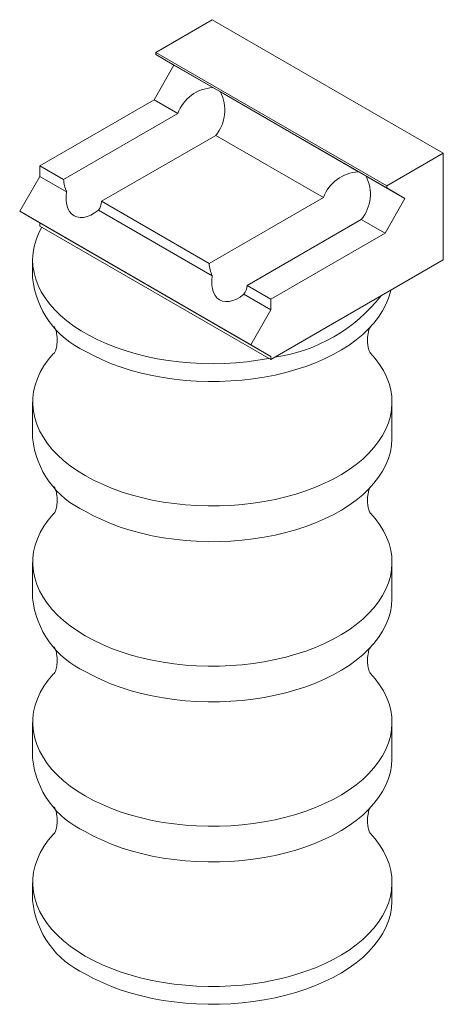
# Model space of a CAD drawing. Units: inches. Extents: x -0.3 to 1.33, y -3.33 to 0.43.
import ezdxf

# ---------------------------------------------------------------- set-up
doc = ezdxf.new("R2010")
doc.units = ezdxf.units.IN
doc.header["$MEASUREMENT"] = 0

msp = doc.modelspace()

# ---------------------------------------------------------------- linework, layer by layer
at = {"color": 7, "linetype": 'Continuous', "lineweight": 15}
for p, q in [((0.4419, 0.4323), (0.2252, 0.3072)), ((1.3258, -0.0779), (0.4419, 0.4323)), ((0.2252, 0.299), (0.2252, 0.3072)), ((1.1091, -0.2031), (0.2252, 0.3072)), ((1.1091, -0.2112), (0.2252, 0.299)), ((0.2252, 0.299), (0.2952, 0.2586)), ((0.2952, 0.2586), (0.2188, 0.1263)), ((0.4443, 0.1726), (0.2952, 0.2586)), ((1.0015, -0.1491), (0.4728, 0.1561)), ((0.2188, 0.1263), (-0.2181, -0.1259)), ((0.3095, 0.074), (0.2188, 0.1263)), ((-0.1275, -0.1783), (0.3095, 0.074)), ((0.4549, -0.0099), (0.0179, -0.2622)), ((0.8667, -0.2477), (0.4549, -0.0099)), ((1.3258, -0.0779), (1.1091, -0.2031)), ((1.3258, -0.4862), (1.3258, -0.0779)), ((-0.2181, -0.1259), (-0.1275, -0.1783)), ((-0.2181, -0.1668), (-0.2181, -0.1259)), ((-0.2952, -0.3003), (-0.2181, -0.1668)), ((-0.1155, -0.226), (-0.2181, -0.1668)), ((1.1791, -0.2516), (1.03, -0.1656)), ((1.1091, -0.2031), (1.1091, -0.2112)), ((1.1091, -0.2112), (1.1791, -0.2516)), ((0.0179, -0.2622), (0.4297, -0.4999)), ((0.4297, -0.4999), (0.8667, -0.2477)), ((1.1791, -0.2516), (1.1027, -0.3839)), ((0.5887, -0.8105), (-0.2952, -0.3003)), ((-0.2181, -0.3448), (-0.2952, -0.3003)), ((0.4417, -0.5477), (0.0059, -0.2961)), ((1.0121, -0.3316), (0.5751, -0.5838)), ((1.1027, -0.3839), (1.0121, -0.3316)), ((0.6657, -0.855), (-0.2181, -0.3448)), ((-0.2181, -0.357), (-0.2181, -0.3448)), ((0.6657, -0.8673), (-0.2181, -0.357)), ((1.1027, -0.3839), (0.6657, -0.6362)), ((-0.2456, -0.4862), (-0.2456, -0.5544)), ((0.6657, -0.8673), (1.3258, -0.4862)), ((0.5751, -0.5838), (0.6657, -0.6362)), ((0.6657, -0.677), (0.5631, -0.6177)), ((0.6657, -0.6362), (0.6657, -0.677)), ((0.6657, -0.677), (0.5887, -0.8105)), ((0.5887, -0.8105), (0.6657, -0.855)), ((0.6657, -0.855), (0.6657, -0.8673)), ((-0.2456, -1.0304), (-0.2456, -1.1668)), ((1.1294, -1.1668), (1.1294, -1.0304)), ((-0.2456, -1.6428), (-0.2456, -1.7792)), ((1.1294, -1.7792), (1.1294, -1.6428)), ((-0.2456, -2.2552), (-0.2456, -2.3916)), ((1.1294, -2.3916), (1.1294, -2.2552)), ((-0.2456, -2.8676), (-0.2456, -2.9358)), ((1.1294, -2.9358), (1.1294, -2.8676))]:
    msp.add_line(p, q, dxfattribs=at)
at = {"color": 7, "linetype": 'Continuous', "lineweight": 15, "flags": 128}
for points in [[(0.4728, 0.1561), (0.4621, 0.1623), (0.4525, 0.1678), (0.4443, 0.1726)], [(1.03, -0.1656), (1.0193, -0.1594), (1.0097, -0.1539), (1.0015, -0.1491)], [(0.0059, -0.2961), (-0.0085, -0.3065), (-0.023, -0.3147), (-0.0373, -0.3204), (-0.0511, -0.3235), (-0.0643, -0.3241), (-0.0764, -0.322), (-0.0873, -0.3174), (-0.0968, -0.3103), (-0.1047, -0.3008), (-0.1108, -0.2891), (-0.1149, -0.2755), (-0.1171, -0.2603), (-0.1173, -0.2437), (-0.1155, -0.226)], [(-0.2106, -0.3613), (-0.223, -0.3854), (-0.2327, -0.4098), (-0.2397, -0.4345), (-0.244, -0.4595), (-0.2456, -0.4845), (-0.2444, -0.5096), (-0.2404, -0.5346), (-0.2338, -0.5593), (-0.2244, -0.5838), (-0.2124, -0.6079), (-0.1978, -0.6315), (-0.1807, -0.6545), (-0.161, -0.6769), (-0.139, -0.6985), (-0.1146, -0.7192), (-0.088, -0.739), (-0.0593, -0.7578), (-0.0286, -0.7756), (0.004, -0.7921), (0.0383, -0.8075), (0.0742, -0.8216), (0.1117, -0.8343), (0.1504, -0.8456), (0.1903, -0.8555), (0.2311, -0.864), (0.2729, -0.8709), (0.3153, -0.8763), (0.3582, -0.8801), (0.4014, -0.8824), (0.4448, -0.8831), (0.4882, -0.8822), (0.5314, -0.8797), (0.5743, -0.8757), (0.6166, -0.8701), (0.6582, -0.8629)], [(0.5631, -0.6177), (0.5487, -0.6282), (0.5342, -0.6363), (0.5199, -0.642), (0.5061, -0.6452), (0.4929, -0.6458), (0.4808, -0.6437), (0.4699, -0.6391), (0.4604, -0.6319), (0.4525, -0.6224), (0.4464, -0.6108), (0.4423, -0.5972), (0.4401, -0.582), (0.4399, -0.5653), (0.4417, -0.5477)], [(-0.0442, -0.835), (-0.0124, -0.8523), (0.0213, -0.8683), (0.0566, -0.8831), (0.0935, -0.8965), (0.1318, -0.9086), (0.1713, -0.9192), (0.2119, -0.9284), (0.2535, -0.9361), (0.2958, -0.9422), (0.3387, -0.9468), (0.382, -0.9498), (0.4256, -0.9512), (0.4692, -0.951), (0.5127, -0.9492), (0.5559, -0.9458), (0.5987, -0.9408), (0.6409, -0.9343), (0.6822, -0.9263), (0.7226, -0.9167), (0.7618, -0.9057), (0.7998, -0.8933), (0.8363, -0.8795), (0.8712, -0.8644), (0.9044, -0.8481), (0.9357, -0.8306), (0.9651, -0.8119), (0.9923, -0.7923), (1.0173, -0.7716), (1.04, -0.7501), (1.0603, -0.7278), (1.0781, -0.7048), (1.0934, -0.6812), (1.106, -0.6571), (1.116, -0.6326), (1.1232, -0.6078), (1.1244, -0.6025)], [(-0.1635, -0.8424), (-0.1666, -0.8458), (-0.1857, -0.8684), (-0.2022, -0.8917), (-0.2162, -0.9156), (-0.2274, -0.9399), (-0.236, -0.9646), (-0.2419, -0.9896), (-0.245, -1.0147), (-0.2454, -1.0399), (-0.2429, -1.065), (-0.2378, -1.09), (-0.2298, -1.1148), (-0.2192, -1.1392), (-0.2059, -1.1632), (-0.19, -1.1867), (-0.1716, -1.2095), (-0.1507, -1.2316), (-0.1274, -1.2529), (-0.1018, -1.2733), (-0.074, -1.2927), (-0.0442, -1.3111)], [(-0.0442, -1.3111), (-0.0124, -1.3283), (0.0213, -1.3443), (0.0566, -1.3591), (0.0935, -1.3725), (0.1318, -1.3846), (0.1713, -1.3953), (0.2119, -1.4044), (0.2535, -1.4121), (0.2958, -1.4182), (0.3387, -1.4228), (0.382, -1.4258), (0.4256, -1.4272), (0.4692, -1.427), (0.5127, -1.4252), (0.5559, -1.4218), (0.5987, -1.4168), (0.6409, -1.4103), (0.6822, -1.4023), (0.7226, -1.3927), (0.7618, -1.3817), (0.7998, -1.3693), (0.8363, -1.3555), (0.8712, -1.3404), (0.9044, -1.3241), (0.9357, -1.3066), (0.9651, -1.2879), (0.9923, -1.2683), (1.0173, -1.2476), (1.04, -1.2261), (1.0603, -1.2038), (1.0781, -1.1808), (1.0934, -1.1572), (1.106, -1.1331), (1.116, -1.1086), (1.1232, -1.0838), (1.1277, -1.0587), (1.1294, -1.0336), (1.1284, -1.0084), (1.1246, -0.9833), (1.118, -0.9584), (1.1088, -0.9338), (1.0968, -0.9096), (1.0822, -0.8858), (1.065, -0.8627), (1.0477, -0.8427)], [(-0.0442, -1.4475), (-0.0124, -1.4647), (0.0213, -1.4807), (0.0566, -1.4955), (0.0935, -1.5089), (0.1318, -1.521), (0.1713, -1.5317), (0.2119, -1.5408), (0.2535, -1.5485), (0.2958, -1.5546), (0.3387, -1.5592), (0.382, -1.5622), (0.4256, -1.5636), (0.4692, -1.5634), (0.5127, -1.5616), (0.5559, -1.5582), (0.5987, -1.5532), (0.6409, -1.5467), (0.6822, -1.5387), (0.7226, -1.5291), (0.7618, -1.5181), (0.7998, -1.5057), (0.8363, -1.4919), (0.8712, -1.4768), (0.9044, -1.4605), (0.9357, -1.443), (0.9651, -1.4243), (0.9923, -1.4047), (1.0173, -1.384), (1.04, -1.3625), (1.0603, -1.3402), (1.0781, -1.3172), (1.0934, -1.2936), (1.106, -1.2695), (1.116, -1.245), (1.1232, -1.2202), (1.1277, -1.1951), (1.1294, -1.17), (1.1294, -1.1668)], [(-0.1635, -1.4548), (-0.1666, -1.4582), (-0.1857, -1.4808), (-0.2022, -1.5041), (-0.2162, -1.528), (-0.2274, -1.5523), (-0.236, -1.577), (-0.2419, -1.602), (-0.245, -1.6271), (-0.2454, -1.6523), (-0.2429, -1.6774), (-0.2378, -1.7024), (-0.2298, -1.7272), (-0.2192, -1.7516), (-0.2059, -1.7756), (-0.19, -1.7991), (-0.1716, -1.8219), (-0.1507, -1.844), (-0.1274, -1.8653), (-0.1018, -1.8857), (-0.074, -1.9051), (-0.0442, -1.9235)], [(-0.0442, -1.9235), (-0.0124, -1.9407), (0.0213, -1.9567), (0.0566, -1.9715), (0.0935, -1.985), (0.1318, -1.997), (0.1713, -2.0077), (0.2119, -2.0168), (0.2535, -2.0245), (0.2958, -2.0306), (0.3387, -2.0352), (0.382, -2.0382), (0.4256, -2.0396), (0.4692, -2.0394), (0.5127, -2.0376), (0.5559, -2.0342), (0.5987, -2.0293), (0.6409, -2.0227), (0.6822, -2.0147), (0.7226, -2.0051), (0.7618, -1.9941), (0.7998, -1.9817), (0.8363, -1.9679), (0.8712, -1.9528), (0.9044, -1.9365), (0.9357, -1.919), (0.9651, -1.9003), (0.9923, -1.8807), (1.0173, -1.86), (1.04, -1.8385), (1.0603, -1.8162), (1.0781, -1.7932), (1.0934, -1.7697), (1.106, -1.7455), (1.116, -1.721), (1.1232, -1.6962), (1.1277, -1.6711), (1.1294, -1.646), (1.1284, -1.6208), (1.1246, -1.5957), (1.118, -1.5708), (1.1088, -1.5462), (1.0968, -1.522), (1.0822, -1.4982), (1.065, -1.4751), (1.0477, -1.4551)], [(-0.0442, -2.0599), (-0.0124, -2.0771), (0.0213, -2.0931), (0.0566, -2.1079), (0.0935, -2.1213), (0.1318, -2.1334), (0.1713, -2.1441), (0.2119, -2.1532), (0.2535, -2.1609), (0.2958, -2.167), (0.3387, -2.1716), (0.382, -2.1746), (0.4256, -2.176), (0.4692, -2.1758), (0.5127, -2.174), (0.5559, -2.1706), (0.5987, -2.1656), (0.6409, -2.1591), (0.6822, -2.1511), (0.7226, -2.1415), (0.7618, -2.1305), (0.7998, -2.1181), (0.8363, -2.1043), (0.8712, -2.0892), (0.9044, -2.0729), (0.9357, -2.0554), (0.9651, -2.0367), (0.9923, -2.0171), (1.0173, -1.9964), (1.04, -1.9749), (1.0603, -1.9526), (1.0781, -1.9296), (1.0934, -1.906), (1.106, -1.8819), (1.116, -1.8574), (1.1232, -1.8326), (1.1277, -1.8075), (1.1294, -1.7824), (1.1294, -1.7792)], [(-0.1635, -2.0672), (-0.1666, -2.0706), (-0.1857, -2.0932), (-0.2022, -2.1165), (-0.2162, -2.1404), (-0.2274, -2.1647), (-0.236, -2.1894), (-0.2419, -2.2144), (-0.245, -2.2395), (-0.2454, -2.2647), (-0.2429, -2.2898), (-0.2378, -2.3148), (-0.2298, -2.3396), (-0.2192, -2.364), (-0.2059, -2.388), (-0.19, -2.4115), (-0.1716, -2.4343), (-0.1507, -2.4564), (-0.1274, -2.4777), (-0.1018, -2.4981), (-0.074, -2.5175), (-0.0442, -2.5359)], [(-0.0442, -2.5359), (-0.0124, -2.5531), (0.0213, -2.5691), (0.0566, -2.5839), (0.0935, -2.5974), (0.1318, -2.6094), (0.1713, -2.6201), (0.2119, -2.6292), (0.2535, -2.6369), (0.2958, -2.643), (0.3387, -2.6476), (0.382, -2.6506), (0.4256, -2.652), (0.4692, -2.6518), (0.5127, -2.65), (0.5559, -2.6466), (0.5987, -2.6417), (0.6409, -2.6351), (0.6822, -2.6271), (0.7226, -2.6175), (0.7618, -2.6065), (0.7998, -2.5941), (0.8363, -2.5803), (0.8712, -2.5652), (0.9044, -2.5489), (0.9357, -2.5314), (0.9651, -2.5127), (0.9923, -2.4931), (1.0173, -2.4724), (1.04, -2.4509), (1.0603, -2.4286), (1.0781, -2.4057), (1.0934, -2.3821), (1.106, -2.3579), (1.116, -2.3334), (1.1232, -2.3086), (1.1277, -2.2835), (1.1294, -2.2584), (1.1284, -2.2332), (1.1246, -2.2081), (1.118, -2.1832), (1.1088, -2.1586), (1.0968, -2.1344), (1.0822, -2.1106), (1.065, -2.0875), (1.0477, -2.0675)], [(-0.0442, -2.6723), (-0.0124, -2.6895), (0.0213, -2.7055), (0.0566, -2.7203), (0.0935, -2.7338), (0.1318, -2.7458), (0.1713, -2.7565), (0.2119, -2.7656), (0.2535, -2.7733), (0.2958, -2.7794), (0.3387, -2.784), (0.382, -2.787), (0.4256, -2.7884), (0.4692, -2.7882), (0.5127, -2.7864), (0.5559, -2.783), (0.5987, -2.7781), (0.6409, -2.7715), (0.6822, -2.7635), (0.7226, -2.7539), (0.7618, -2.7429), (0.7998, -2.7305), (0.8363, -2.7167), (0.8712, -2.7016), (0.9044, -2.6853), (0.9357, -2.6678), (0.9651, -2.6491), (0.9923, -2.6295), (1.0173, -2.6088), (1.04, -2.5873), (1.0603, -2.565), (1.0781, -2.542), (1.0934, -2.5185), (1.106, -2.4943), (1.116, -2.4698), (1.1232, -2.445), (1.1277, -2.4199), (1.1294, -2.3948), (1.1294, -2.3916)], [(-0.1635, -2.6796), (-0.1666, -2.683), (-0.1857, -2.7056), (-0.2022, -2.7289), (-0.2162, -2.7528), (-0.2274, -2.7771), (-0.236, -2.8018), (-0.2419, -2.8268), (-0.245, -2.8519), (-0.2454, -2.8771), (-0.2429, -2.9022), (-0.2378, -2.9272), (-0.2298, -2.952), (-0.2192, -2.9764), (-0.2059, -3.0004), (-0.19, -3.0239), (-0.1716, -3.0467), (-0.1507, -3.0688), (-0.1274, -3.0901), (-0.1018, -3.1105), (-0.074, -3.1299), (-0.0442, -3.1483)], [(-0.0442, -3.1483), (-0.0124, -3.1655), (0.0213, -3.1815), (0.0566, -3.1963), (0.0935, -3.2098), (0.1318, -3.2218), (0.1713, -3.2325), (0.2119, -3.2416), (0.2535, -3.2493), (0.2958, -3.2554), (0.3387, -3.26), (0.382, -3.263), (0.4256, -3.2644), (0.4692, -3.2642), (0.5127, -3.2624), (0.5559, -3.259), (0.5987, -3.2541), (0.6409, -3.2475), (0.6822, -3.2395), (0.7226, -3.23), (0.7618, -3.2189), (0.7998, -3.2065), (0.8363, -3.1927), (0.8712, -3.1777), (0.9044, -3.1613), (0.9357, -3.1438), (0.9651, -3.1252), (0.9923, -3.1055), (1.0173, -3.0848), (1.04, -3.0633), (1.0603, -3.0411), (1.0781, -3.0181), (1.0934, -2.9945), (1.106, -2.9704), (1.116, -2.9458), (1.1232, -2.921), (1.1277, -2.8959), (1.1294, -2.8708), (1.1284, -2.8456), (1.1246, -2.8205), (1.118, -2.7956), (1.1088, -2.771), (1.0968, -2.7468), (1.0822, -2.7231), (1.065, -2.6999), (1.0477, -2.6799)], [(-0.0442, -3.2165), (-0.0124, -3.2337), (0.0213, -3.2497), (0.0566, -3.2645), (0.0935, -3.278), (0.1318, -3.29), (0.1713, -3.3007), (0.2119, -3.3098), (0.2535, -3.3175), (0.2958, -3.3236), (0.3387, -3.3282), (0.382, -3.3312), (0.4256, -3.3326), (0.4692, -3.3324), (0.5127, -3.3306), (0.5559, -3.3272), (0.5987, -3.3223), (0.6409, -3.3157), (0.6822, -3.3077), (0.7226, -3.2981), (0.7618, -3.2871), (0.7998, -3.2747), (0.8363, -3.2609), (0.8712, -3.2458), (0.9044, -3.2295), (0.9357, -3.212), (0.9651, -3.1933), (0.9923, -3.1737), (1.0173, -3.153), (1.04, -3.1315), (1.0603, -3.1092), (1.0781, -3.0863), (1.0934, -3.0627), (1.106, -3.0386), (1.116, -3.014), (1.1232, -2.9892), (1.1277, -2.9641), (1.1294, -2.939), (1.1294, -2.9358)]]:
    msp.add_lwpolyline(points, dxfattribs=at)
at = {"color": 7, "linetype": 'Continuous', "lineweight": 15}
for centre, radius, start, end in [((0.4523, 0.0202), 0.1526, 93.02, 159.3518), ((0.3369, 0.0868), 0.1526, 320.6468, 26.9831), ((1.0095, -0.3015), 0.1526, 93.02, 159.3518), ((0.0151, -0.1678), 0.1429, 184.186, 204.0262), ((0.8941, -0.2348), 0.1526, 320.6468, 26.9831), ((-0.0388, -0.2612), 0.0567, 322.0206, 358.9906), ((0.5723, -0.4895), 0.1429, 184.186, 204.0262), ((0.0977, -0.5207), 0.3449, 185.6152, 245.705), ((0.5184, -0.5828), 0.0567, 322.0206, 358.9906), ((0.5911, -0.2341), 0.6307, 278.2324, 321.7622), ((0.0977, -1.1331), 0.3449, 185.6152, 245.705), ((0.0977, -1.7455), 0.3449, 185.6152, 245.705), ((0.0977, -2.3579), 0.3449, 185.6152, 245.705), ((0.0977, -2.9021), 0.3449, 185.6152, 245.705)]:
    msp.add_arc(centre, radius, start, end, dxfattribs=at)
for points, knots in [([(-0.1629, -0.7417), (-0.1628, -0.7419), (-0.1625, -0.7423), (-0.1609, -0.7455), (-0.1586, -0.751), (-0.1559, -0.7592), (-0.1535, -0.7701), (-0.1518, -0.7841), (-0.1517, -0.7997), (-0.1534, -0.8142), (-0.1559, -0.8256), (-0.1586, -0.8338), (-0.1608, -0.8393), (-0.1625, -0.8426), (-0.1627, -0.8429), (-0.1628, -0.843)], [0, 0, 0, 0, 0.061053, 0.127077, 0.196823, 0.271558, 0.35309, 0.444066, 0.547799, 0.644585, 0.728413, 0.803653, 0.872799, 0.937507, 1, 1, 1, 1]), ([(1.0466, -0.8429), (1.0467, -0.8429), (1.0468, -0.8431), (1.0456, -0.8411), (1.0437, -0.8369), (1.0411, -0.8301), (1.0385, -0.8205), (1.0363, -0.808), (1.0354, -0.7926), (1.0363, -0.777), (1.0387, -0.7637), (1.0413, -0.7542), (1.0438, -0.7476), (1.045, -0.7452), (1.0455, -0.7441)], [0, 0, 0, 0, 0.032196, 0.103512, 0.178391, 0.258028, 0.344087, 0.43899, 0.546179, 0.668256, 0.766232, 0.853063, 0.932116, 1, 1, 1, 1]), ([(-0.1629, -1.3541), (-0.1628, -1.3543), (-0.1625, -1.3547), (-0.1609, -1.3579), (-0.1586, -1.3634), (-0.1559, -1.3716), (-0.1535, -1.3825), (-0.1518, -1.3965), (-0.1517, -1.4121), (-0.1534, -1.4266), (-0.1559, -1.438), (-0.1586, -1.4462), (-0.1608, -1.4517), (-0.1625, -1.455), (-0.1627, -1.4553), (-0.1628, -1.4555)], [0, 0, 0, 0, 0.061053, 0.127077, 0.196823, 0.271558, 0.35309, 0.444066, 0.547799, 0.644585, 0.728413, 0.803653, 0.872799, 0.937507, 1, 1, 1, 1]), ([(1.0466, -1.4553), (1.0467, -1.4553), (1.0468, -1.4555), (1.0456, -1.4535), (1.0437, -1.4493), (1.0411, -1.4425), (1.0385, -1.4329), (1.0363, -1.4204), (1.0354, -1.405), (1.0363, -1.3894), (1.0387, -1.3761), (1.0413, -1.3666), (1.0438, -1.36), (1.045, -1.3576), (1.0455, -1.3565)], [0, 0, 0, 0, 0.032196, 0.103512, 0.178391, 0.258028, 0.344087, 0.43899, 0.546179, 0.668256, 0.766232, 0.853063, 0.932116, 1, 1, 1, 1]), ([(-0.1629, -1.9665), (-0.1628, -1.9667), (-0.1625, -1.9671), (-0.1609, -1.9703), (-0.1586, -1.9758), (-0.1559, -1.984), (-0.1535, -1.995), (-0.1518, -2.0089), (-0.1517, -2.0245), (-0.1534, -2.039), (-0.1559, -2.0504), (-0.1586, -2.0586), (-0.1608, -2.0641), (-0.1625, -2.0674), (-0.1627, -2.0677), (-0.1628, -2.0679)], [0, 0, 0, 0, 0.061053, 0.127077, 0.196823, 0.271558, 0.35309, 0.444066, 0.547799, 0.644585, 0.728413, 0.803653, 0.872799, 0.937507, 1, 1, 1, 1]), ([(1.0466, -2.0677), (1.0467, -2.0677), (1.0468, -2.0679), (1.0456, -2.0659), (1.0437, -2.0617), (1.0411, -2.0549), (1.0385, -2.0453), (1.0363, -2.0328), (1.0354, -2.0174), (1.0363, -2.0018), (1.0387, -1.9885), (1.0413, -1.979), (1.0438, -1.9724), (1.045, -1.97), (1.0455, -1.9689)], [0, 0, 0, 0, 0.032196, 0.103512, 0.178391, 0.258028, 0.344087, 0.43899, 0.546179, 0.668256, 0.766232, 0.853063, 0.932116, 1, 1, 1, 1]), ([(-0.1629, -2.579), (-0.1628, -2.5791), (-0.1625, -2.5795), (-0.1609, -2.5827), (-0.1586, -2.5882), (-0.1559, -2.5964), (-0.1535, -2.6074), (-0.1518, -2.6214), (-0.1517, -2.6369), (-0.1534, -2.6514), (-0.1559, -2.6628), (-0.1586, -2.6711), (-0.1608, -2.6765), (-0.1625, -2.6798), (-0.1627, -2.6801), (-0.1628, -2.6803)], [0, 0, 0, 0, 0.061053, 0.127077, 0.196823, 0.271558, 0.35309, 0.444066, 0.547799, 0.644585, 0.728413, 0.803653, 0.872799, 0.937507, 1, 1, 1, 1]), ([(1.0466, -2.6801), (1.0467, -2.6801), (1.0468, -2.6803), (1.0456, -2.6783), (1.0437, -2.6741), (1.0411, -2.6673), (1.0385, -2.6577), (1.0363, -2.6453), (1.0354, -2.6298), (1.0363, -2.6142), (1.0387, -2.6009), (1.0413, -2.5914), (1.0438, -2.5848), (1.045, -2.5824), (1.0455, -2.5813)], [0, 0, 0, 0, 0.032196, 0.103512, 0.178391, 0.258028, 0.344087, 0.43899, 0.546179, 0.668256, 0.766232, 0.853063, 0.932116, 1, 1, 1, 1])]:
    msp.add_open_spline(points, degree=3, knots=knots, dxfattribs=at)

doc.saveas('drawing.dxf')
